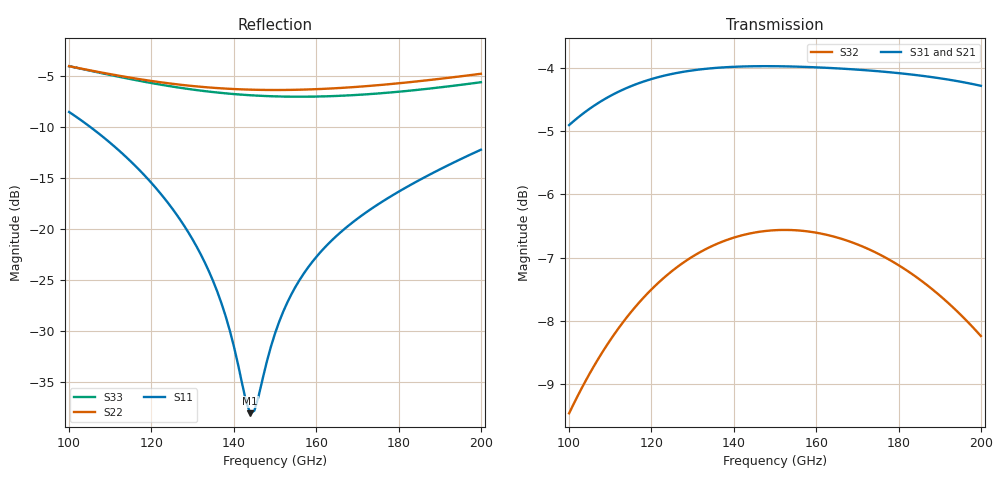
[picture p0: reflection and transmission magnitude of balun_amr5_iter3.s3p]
! Created with skrf 2.2.0 (http://scikit-rf.org).
# GHz S DB R 50.0
! Port[1] = P1
! Port[2] = P2
! Port[3] = P3
!freq dBS11 angS11 dBS12 angS12 dBS13 angS13
! dBS21 angS21 dBS22 angS22 dBS23 angS23
! dBS31 angS31 dBS32 angS32 dBS33 angS33
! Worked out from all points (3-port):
!   101 points, 100 GHz to 200 GHz, reference 50 ohm
!   strongest paths, dB at 100 GHz, 125 GHz, 150 GHz, 175 GHz, 200 GHz:
!     S31: -4.9, -4.1, -4.0, -4.1, -4.3
!     S21: -4.7, -4.0, -4.0, -4.2, -4.7
!     S32: -9.5, -7.2, -6.6, -6.9, -8.2
!   lowest |S11| = -38.0 dB at 144 GHz (marker M1), VSWR 1.03, Z = 48.8 + j0.393 ohm
!   |S11| at or under -10 dB: 105 GHz to end of sweep
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100  -8.56 129.0  -4.65 -11.7  -4.91 164.5
     -4.65 -11.7  -4.09 60.1  -9.46 90.4
     -4.91 164.5  -9.46 90.4  -4.08 50.2
117  -14.21 107.5  -4.08 -37.9  -4.24 136.9
     -4.08 -37.9  -5.34 44.9  -7.71 64.7
     -4.24 136.9  -7.71 64.7  -5.51 32.5
129  -20.36 98.4  -3.95 -54.7  -4.05 119.0
     -3.95 -54.7  -5.98 35.8  -7.02 47.8
     -4.05 119.0  -7.02 47.8  -6.31 22.0
137  -27.27 100.7  -3.94 -65.3  -4.00 107.8
     -3.94 -65.3  -6.25 30.1  -6.75 37.2
     -4.00 107.8  -6.75 37.2  -6.70 15.7
144  -38.02 161.3  -3.96 -74.2  -3.98 98.3
     -3.96 -74.2  -6.38 25.1  -6.62 28.2
     -3.98 98.3  -6.62 28.2  -6.92 10.3
145  -37.75 -175.8  -3.96 -75.5  -3.98 97.0
     -3.96 -75.5  -6.39 24.4  -6.60 26.9
     -3.98 97.0  -6.60 26.9  -6.95 9.6
150  -30.22 -128.6  -3.99 -81.7  -3.98 90.4
     -3.99 -81.7  -6.41 20.8  -6.57 20.7
     -3.98 90.4  -6.57 20.7  -7.03 5.8
156  -24.96 -120.8  -4.03 -89.0  -3.98 82.6
     -4.03 -89.0  -6.38 16.4  -6.57 13.3
     -3.98 82.6  -6.57 13.3  -7.07 1.3
165  -20.66 -119.9  -4.11 -99.8  -4.01 71.2
     -4.11 -99.8  -6.23 9.4  -6.68 2.5
     -4.01 71.2  -6.68 2.5  -6.99 -5.7
200  -12.25 -133.2  -4.69 -142.0  -4.29 26.8
     -4.69 -142.0  -4.83 -21.4  -8.24 -38.8
     -4.29 26.8  -8.24 -38.8  -5.65 -35.6
